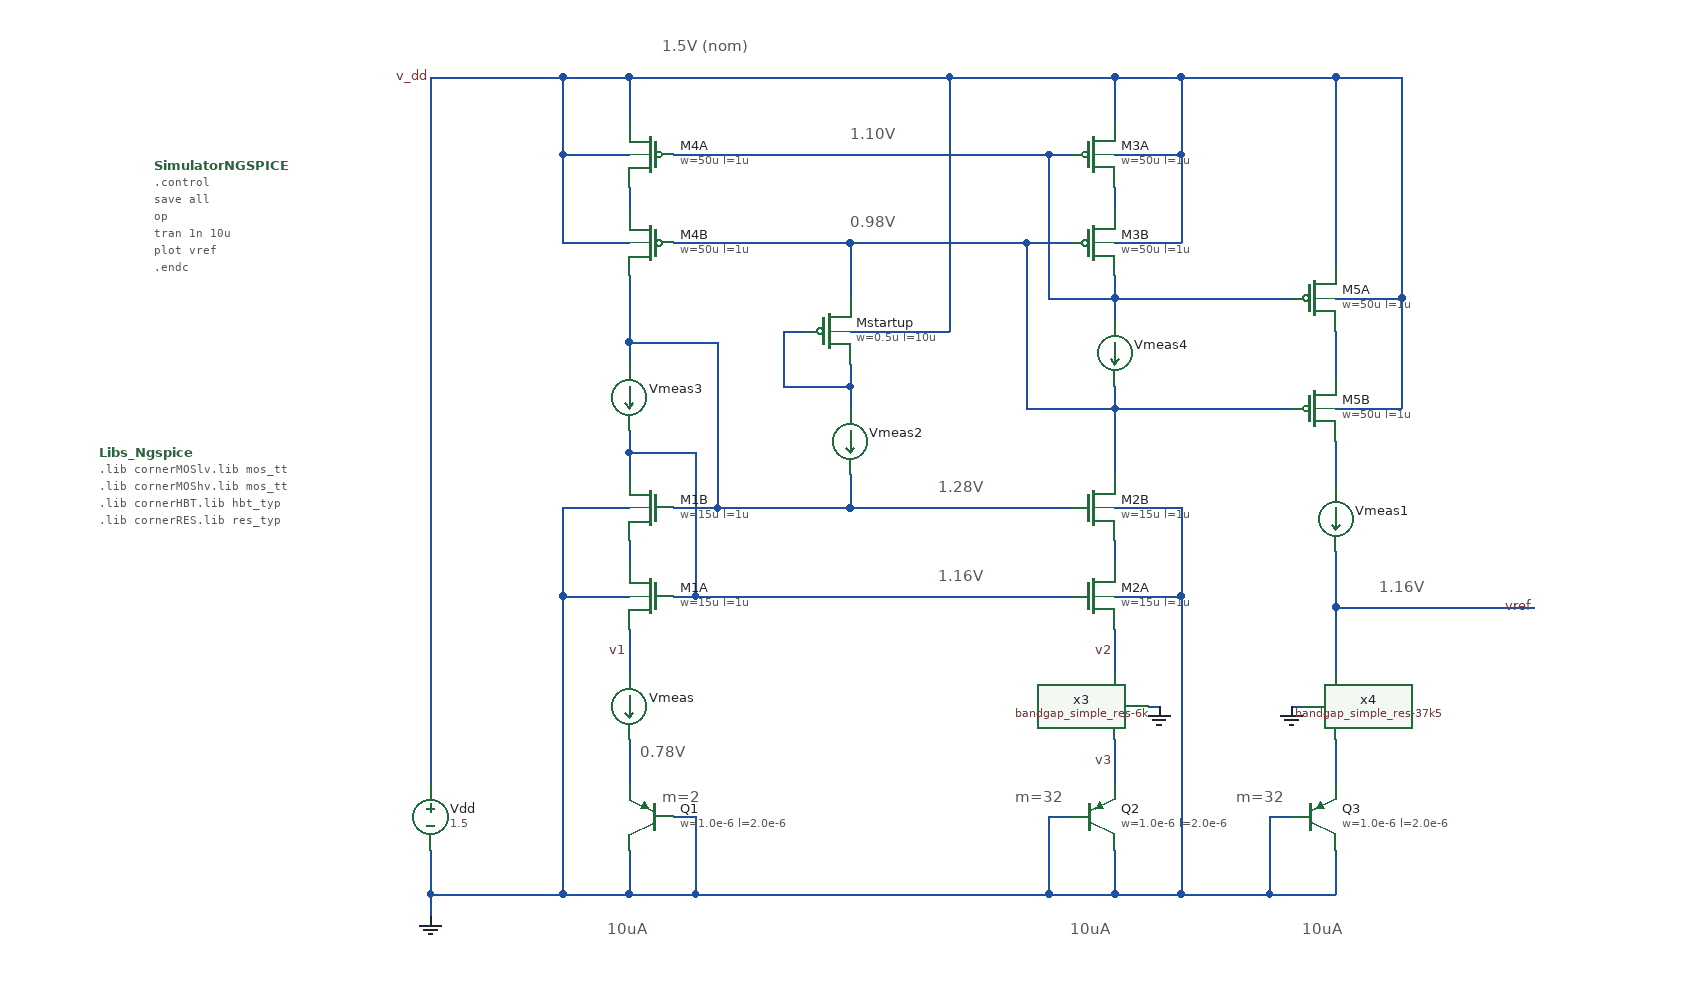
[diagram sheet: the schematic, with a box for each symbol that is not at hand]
v {xschem version=3.4.8RC file_version=1.2}
G {}
K {}
V {}
S {}
F {}
E {}
T {m=32} 600 -530 0 0 0.4 0.4 {}
T {10uA} 230 -410 0 0 0.4 0.4 {}
T {10uA} 650 -410 0 0 0.4 0.4 {}
T {10uA} 860 -410 0 0 0.4 0.4 {}
T {m=2} 280 -530 0 0 0.4 0.4 {}
T {m=32} 800 -530 0 0 0.4 0.4 {}
T {1.16V} 930 -720 0 0 0.4 0.4 {}
T {1.16V} 530 -730 0 0 0.4 0.4 {}
T {1.28V} 530 -810 0 0 0.4 0.4 {}
T {1.10V} 450 -1130 0 0 0.4 0.4 {}
T {0.98V} 450 -1050 0 0 0.4 0.4 {}
T {0.78V} 260 -570 0 0 0.4 0.4 {}
T {1.5V (nom)} 280 -1210 0 0 0.4 0.4 {}
N 70 -430 70 -410 {
lab=GND}
N 70 -470 70 -430 {
lab=GND}
N 690 -470 690 -430 {lab=GND}
N 250 -470 250 -430 {lab=GND}
N 630 -500 650 -500 {lab=GND}
N 630 -500 630 -430 {lab=GND}
N 290 -500 310 -500 {lab=GND}
N 310 -500 310 -430 {lab=GND}
N 250 -430 310 -430 {
lab=GND}
N 690 -570 690 -530 {lab=v3}
N 250 -1170 250 -1130 {lab=v_dd}
N 540 -1170 690 -1170 {lab=v_dd}
N 690 -1170 690 -1130 {lab=v_dd}
N 190 -1170 250 -1170 {lab=v_dd}
N 630 -1100 650 -1100 {lab=#net1}
N 290 -700 310 -700 {lab=#net2}
N 190 -1100 250 -1100 {lab=v_dd}
N 190 -1170 190 -1100 {lab=v_dd}
N 70 -1170 190 -1170 {lab=v_dd}
N 690 -1100 750 -1100 {lab=v_dd}
N 750 -1170 750 -1100 {lab=v_dd}
N 690 -1170 750 -1170 {lab=v_dd}
N 190 -700 250 -700 {lab=GND}
N 190 -430 250 -430 {
lab=GND}
N 690 -700 750 -700 {lab=GND}
N 750 -430 830 -430 {lab=GND}
N 830 -430 890 -430 {
lab=GND}
N 890 -470 890 -430 {lab=GND}
N 830 -500 850 -500 {lab=GND}
N 830 -500 830 -430 {lab=GND}
N 890 -570 890 -530 {lab=#net3}
N 750 -1170 890 -1170 {lab=v_dd}
N 890 -690 890 -630 {lab=vref}
N 890 -1170 950 -1170 {lab=v_dd}
N 890 -690 1070 -690 {lab=vref}
N 250 -570 250 -530 {lab=#net4}
N 890 -740 890 -690 {lab=vref}
N 690 -750 690 -730 {lab=#net5}
N 690 -780 750 -780 {lab=GND}
N 750 -780 750 -700 {lab=GND}
N 250 -750 250 -730 {lab=#net6}
N 190 -780 250 -780 {lab=GND}
N 190 -780 190 -700 {lab=GND}
N 250 -830 310 -830 {lab=#net2}
N 250 -830 250 -810 {lab=#net2}
N 310 -830 310 -700 {lab=#net2}
N 330 -930 330 -780 {lab=#net7}
N 290 -780 330 -780 {lab=#net7}
N 250 -930 330 -930 {lab=#net7}
N 250 -990 250 -930 {lab=#net7}
N 250 -1070 250 -1050 {lab=#net8}
N 610 -1020 650 -1020 {lab=#net9}
N 690 -1070 690 -1050 {lab=#net10}
N 690 -1020 750 -1020 {lab=v_dd}
N 750 -1100 750 -1020 {lab=v_dd}
N 190 -1020 250 -1020 {lab=v_dd}
N 190 -1100 190 -1020 {lab=v_dd}
N 630 -970 690 -970 {lab=#net1}
N 610 -1020 610 -870 {lab=#net9}
N 690 -870 850 -870 {lab=#net9}
N 690 -870 690 -810 {lab=#net9}
N 630 -1100 630 -970 {lab=#net1}
N 690 -990 690 -970 {lab=#net1}
N 690 -970 850 -970 {lab=#net1}
N 70 -1170 70 -530 {lab=v_dd}
N 250 -670 250 -630 {lab=v1}
N 190 -700 190 -430 {lab=GND}
N 690 -670 690 -630 {lab=v2}
N 750 -700 750 -430 {lab=GND}
N 610 -870 690 -870 {lab=#net9}
N 70 -430 190 -430 {
lab=GND}
N 690 -430 750 -430 {lab=GND}
N 890 -1170 890 -1000 {lab=v_dd}
N 950 -970 950 -870 {lab=v_dd}
N 890 -870 950 -870 {lab=v_dd}
N 890 -970 950 -970 {lab=v_dd}
N 950 -1170 950 -970 {lab=v_dd}
N 890 -940 890 -900 {lab=#net11}
N 890 -840 890 -800 {lab=#net12}
N 630 -430 690 -430 {lab=GND}
N 310 -430 630 -430 {
lab=GND}
N 290 -1100 630 -1100 {lab=#net1}
N 390 -940 410 -940 {lab=#net13}
N 450 -910 450 -890 {lab=#net13}
N 310 -700 650 -700 {lab=#net2}
N 450 -1020 610 -1020 {lab=#net9}
N 450 -1020 450 -970 {lab=#net9}
N 290 -1020 450 -1020 {lab=#net9}
N 450 -940 540 -940 {lab=v_dd}
N 250 -1170 540 -1170 {lab=v_dd}
N 390 -890 450 -890 {lab=#net13}
N 390 -940 390 -890 {lab=#net13}
N 450 -780 650 -780 {lab=#net7}
N 450 -810 450 -780 {lab=#net7}
N 330 -780 450 -780 {lab=#net7}
N 540 -1170 540 -940 {lab=v_dd}
N 450 -890 450 -870 {lab=#net13}
N 850 -600 860 -600 {lab=GND}
N 720 -600 730 -600 {lab=GND}
N 250 -930 250 -910 {lab=#net7}
N 250 -850 250 -830 {lab=#net2}
N 690 -970 690 -950 {lab=#net1}
N 690 -890 690 -870 {lab=#net9}
C {simulator_commands_shown.sym} -230 -830 0 0 {
name=Libs_Ngspice
simulator=ngspice
only_toplevel=false
value="
.lib cornerMOSlv.lib mos_tt
.lib cornerMOShv.lib mos_tt
.lib cornerHBT.lib hbt_typ
.lib cornerRES.lib res_typ
"
      }
C {simulator_commands_shown.sym} -180 -1090 0 0 {name=SimulatorNGSPICE
simulator=ngspice
only_toplevel=false 
value="
.control
save all 
op
tran 1n 10u
plot vref

.endc
"
}
C {devices/vsource.sym} 70 -500 0 0 {name=Vdd value=1.5}
C {devices/gnd.sym} 70 -410 0 0 {name=l3 lab=GND}
C {devices/lab_pin.sym} 70 -1170 0 0 {name=p2 sig_type=std_logic lab=v_dd}
C {sg13g2_pr/pnpMPA.sym} 270 -500 0 1 {name=Q1
model=pnpMPA
spiceprefix=X
w=1.0e-6
l=2.0e-6
m=2
}
C {sg13g2_pr/pnpMPA.sym} 670 -500 0 0 {name=Q2
model=pnpMPA
spiceprefix=X
w=1.0e-6
l=2.0e-6
m=32
}
C {sg13g2_pr/sg13_lv_nmos.sym} 270 -700 0 1 {name=M1A
l=1u
w=15u
ng=3
m=1
model=sg13_lv_nmos
spiceprefix=X
}
C {sg13g2_pr/pnpMPA.sym} 870 -500 0 0 {name=Q3
model=pnpMPA
spiceprefix=X
w=1.0e-6
l=2.0e-6
m=32
}
C {devices/lab_wire.sym} 1070 -690 0 0 {name=p3 sig_type=std_logic lab=vref}
C {devices/ammeter.sym} 250 -600 0 0 {name=Vmeas savecurrent=true spice_ignore=0}
C {devices/ammeter.sym} 890 -770 0 0 {name=Vmeas1 savecurrent=true spice_ignore=0}
C {devices/lab_pin.sym} 690 -650 0 0 {name=p4 sig_type=std_logic lab=v2}
C {devices/lab_pin.sym} 690 -550 0 0 {name=p5 sig_type=std_logic lab=v3}
C {devices/lab_pin.sym} 250 -650 0 0 {name=p6 sig_type=std_logic lab=v1}
C {sg13g2_pr/sg13_lv_pmos.sym} 270 -1020 0 1 {name=M4B
l=1u
w=50u
ng=10
m=1
model=sg13_lv_pmos
spiceprefix=X
}
C {sg13g2_pr/sg13_lv_nmos.sym} 270 -780 0 1 {name=M1B
l=1u
w=15u
ng=3
m=1
model=sg13_lv_nmos
spiceprefix=X
}
C {sg13g2_pr/sg13_lv_nmos.sym} 670 -700 0 0 {name=M2A
l=1u
w=15u
ng=3
m=1
model=sg13_lv_nmos
spiceprefix=X
}
C {sg13g2_pr/sg13_lv_nmos.sym} 670 -780 0 0 {name=M2B
l=1u
w=15u
ng=3
m=1
model=sg13_lv_nmos
spiceprefix=X
}
C {sg13g2_pr/sg13_lv_pmos.sym} 270 -1100 0 1 {name=M4A
l=1u
w=50u
ng=10
m=1
model=sg13_lv_pmos
spiceprefix=X
}
C {sg13g2_pr/sg13_lv_pmos.sym} 670 -1020 0 0 {name=M3B
l=1u
w=50u
ng=10
m=1
model=sg13_lv_pmos
spiceprefix=X
}
C {sg13g2_pr/sg13_lv_pmos.sym} 670 -1100 0 0 {name=M3A
l=1u
w=50u
ng=10
m=1
model=sg13_lv_pmos
spiceprefix=X
}
C {sg13g2_pr/sg13_lv_pmos.sym} 870 -970 0 0 {name=M5A
l=1u
w=50u
ng=10
m=1
model=sg13_lv_pmos
spiceprefix=X
}
C {sg13g2_pr/sg13_lv_pmos.sym} 870 -870 0 0 {name=M5B
l=1u
w=50u
ng=10
m=1
model=sg13_lv_pmos
spiceprefix=X
}
C {sg13g2_pr/sg13_lv_pmos.sym} 430 -940 0 0 {name=Mstartup
l=10u
w=0.5u
ng=1
m=1
model=sg13_lv_pmos
spiceprefix=X
}
C {devices/ammeter.sym} 450 -840 0 0 {name=Vmeas2 savecurrent=true spice_ignore=0}
C {devices/gnd.sym} 730 -600 3 0 {name=l2 lab=GND}
C {devices/gnd.sym} 850 -600 1 1 {name=l4 lab=GND}
C {/foss/designs/analog-circuit-design/xschem/bandgap_simple_res-6k.sym} 690 -570 0 1 {name=x3}
C {/foss/designs/analog-circuit-design/xschem/bandgap_simple_res-37k5.sym} 890 -570 0 0 {name=x4}
C {devices/ammeter.sym} 250 -880 0 0 {name=Vmeas3 savecurrent=true spice_ignore=0}
C {devices/ammeter.sym} 690 -920 0 0 {name=Vmeas4 savecurrent=true spice_ignore=0}
